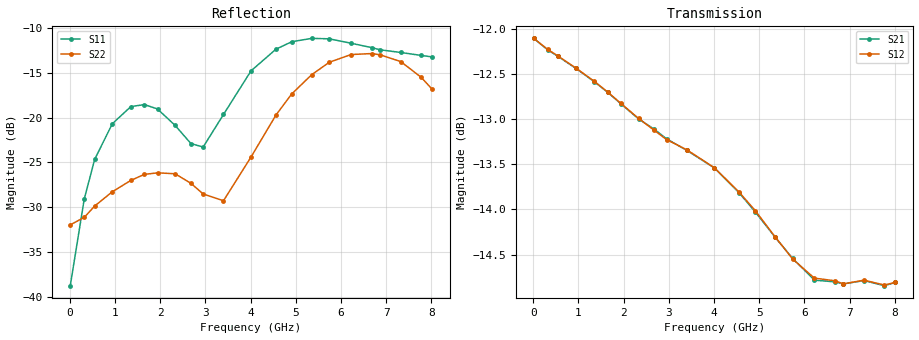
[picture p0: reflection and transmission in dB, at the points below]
!Agilent Technologies,E5071B,MY42404982,A.09.10
!Date: Mon Oct 20 13:32:07 2025
!Data & Calibration Information:
!Freq	S11:SOLT2(ON)	S21:SOLT2(ON)	S12:SOLT2(ON)	S22:SOLT2(ON)
# Hz S RI R 50
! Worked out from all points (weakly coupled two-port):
!   801 points, 10 MHz to 8.01 GHz, reference 50 ohm
!   highest |S21| = -12.11 dB at 10 MHz (marker M1); lowest = -14.8 dB at 7.77 GHz (marker M2)
!   lowest |S11| = -38.7 dB at 10 MHz (marker M3), VSWR 1.02, Z = 48.9 - j0.175 ohm
!   |S11| at or under -10 dB: start of sweep to end of sweep
!   |S22| runs from -32.0 to -12.8 dB; largest |S21 - S12| = 0.0019
!   S11 on the Smith chart (normalised r, x): 10 MHz: 0.98, -0.00; 4.56 GHz: 0.62, +0.11; 5.74 GHz: 1.13, +0.59; 6.86 GHz: 1.35, -0.45; 8.01 GHz: 0.66, -0.12
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1e7  -0.0114 -0.00179  0.248 -0.00539  0.248 -0.00552  0.0252 -0.000999
3.2e8  -0.0226 -0.027  0.2036 -0.1353  0.2037 -0.1354  0.0224 -0.0164
5.5e8  -0.043 -0.0396  0.1308 -0.2041  0.1307 -0.2043  0.014 -0.0289
9.4e8  -0.088 -0.0283  -0.0309 -0.2368  -0.0309 -0.2369  -0.0153 -0.0354
1.35e9  -0.1125 0.0248  -0.1782 -0.1528  -0.1783 -0.1529  -0.0427 -0.013
1.65e9  -0.0946 0.0709  -0.228 -0.0405  -0.2281 -0.0404  -0.046 0.0145
1.94e9  -0.0516 0.0991  -0.2153 0.0757  -0.2154 0.0758  -0.031 0.0382
2.33e9  0.0196 0.0883  -0.1165 0.1912  -0.1166 0.1913  0.00316 0.0485
2.68e9  0.0625 0.035  0.014 0.2205  0.0141 0.2202  0.0301 0.0307
2.95e9  0.0644 -0.0234  0.1113 0.1878  0.1112 0.1876  0.0367 0.00771
3.4e9  -0.000451 -0.1041  0.2083 0.0536  0.2085 0.0535  0.0164 -0.0302
4.01e9  -0.162 -0.0838  0.1438 -0.1535  0.1441 -0.1533  -0.0518 -0.0309
4.56e9  -0.2272 0.0797  -0.0432 -0.1991  -0.0431 -0.1993  -0.0942 0.0423
4.91e9  -0.1773 0.197  -0.1463 -0.1348  -0.1461 -0.1355  -0.0803 0.1092
5.35e9  -0.0282 0.2754  -0.1926 0.0033  -0.1927 0.00286  -0.00279 0.1734
5.74e9  0.1272 0.2441  -0.1451 0.1187  -0.145 0.1186  0.0986 0.1781
6.22e9  0.2444 0.0892  -0.0143 0.1818  -0.0126 0.1824  0.2044 0.0936
6.68e9  0.2254 -0.0981  0.1179 0.1386  0.1184 0.1385  0.2247 -0.0376
6.86e9  0.1792 -0.1583  0.1537 0.0965  0.1541 0.0959  0.2065 -0.0877
7.32e9  0.00843 -0.2308  0.1775 -0.0414  0.1775 -0.0418  0.1107 -0.1732
7.77e9  -0.154 -0.1605  0.0967 -0.1531  0.0965 -0.1534  -0.00897 -0.168
8.01e9  -0.2012 -0.0846  0.0257 -0.18  0.0259 -0.18  -0.0581 -0.1325
